VERSION 5.8 ;
BUSBITCHARS "[]" ;
DIVIDERCHAR "/" ;

# Buffer based on BUF_X1 with the output pin on metal3. Used to test
# buffer removal merging routes that reach the buffer gcell on disjoint
# layer ranges.
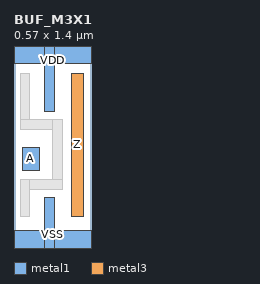
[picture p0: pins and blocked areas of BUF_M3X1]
MACRO BUF_M3X1
  CLASS CORE ;
  ORIGIN 0 0 ;
  SIZE 0.57 BY 1.4 ;
  SYMMETRY X Y ;
  SITE FreePDK45_38x28_10R_NP_162NW_34O ;
  PIN A
    DIRECTION INPUT ;
    USE SIGNAL ;
    PORT
      LAYER metal1 ;
        RECT 0.06 0.525 0.19 0.7 ;
    END
  END A
  PIN Z
    DIRECTION OUTPUT ;
    USE SIGNAL ;
    PORT
      LAYER metal3 ;
        RECT 0.42 0.19 0.51 1.24 ;
    END
  END Z
  PIN VDD
    DIRECTION INOUT ;
    USE POWER ;
    SHAPE ABUTMENT ;
    PORT
      LAYER metal1 ;
        RECT 0 1.315 0.57 1.485 ;
        RECT 0.225 0.965 0.295 1.485 ;
    END
  END VDD
  PIN VSS
    DIRECTION INOUT ;
    USE GROUND ;
    SHAPE ABUTMENT ;
    PORT
      LAYER metal1 ;
        RECT 0 -0.085 0.57 0.085 ;
        RECT 0.225 -0.085 0.295 0.325 ;
    END
  END VSS
  OBS
    LAYER metal1 ;
      RECT 0.045 0.83 0.115 1.24 ;
      RECT 0.045 0.83 0.355 0.9 ;
      RECT 0.285 0.39 0.355 0.9 ;
      RECT 0.045 0.39 0.355 0.46 ;
      RECT 0.045 0.19 0.115 0.46 ;
  END
END BUF_M3X1

END LIBRARY
